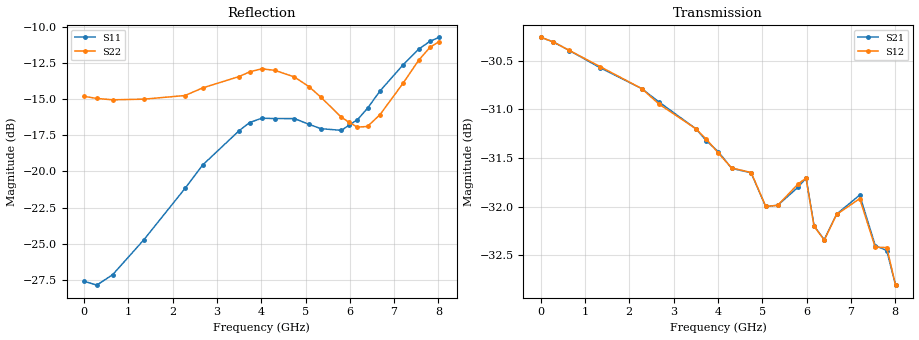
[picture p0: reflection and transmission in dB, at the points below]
! DEVICE ID: PE43712
! File Path: z:\PE43713\PE43713_CHAR_NOM_04292014\AMB\3p300\LS_ATT_29p00dB\PE43713_AMB_3p300V_3p000V_0p000V_LS_ATT_29p00dB_S2P_SN_10_A0139A.s2p
! Serial: 10
! Lot: A0139A
! Temp: 25C
! VDD: 3.300
! VSS: 0.000
! Control_Hi: 3.000
! Control_Lo: 0.000
! Attenuation Step: 29.00dB
! Port 1: RF1
! Port 2: RF2
! ThroughPath:1-2
! IDD: 0.0001456106
! ISS: -1.121e-007
#  Hz  S  RI  R  50
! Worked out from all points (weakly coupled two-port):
!   801 points, 10 MHz to 8.01 GHz, reference 50 ohm
!   highest |S21| = -30.26 dB at 10 MHz (marker M1); lowest = -32.8 dB at 8.01 GHz (marker M2)
!   lowest |S11| = -27.9 dB at 290 MHz (marker M3), VSWR 1.08, Z = 46.3 + j1.23 ohm
!   |S11| at or under -10 dB: start of sweep to end of sweep
!   |S22| runs from -16.9 to -11.0 dB; largest |S21 - S12| = 0.00012
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1e7  -0.0416 0.000898  0.0307 -0.000144  0.0307 -0.000132  -0.1822 0.0013
2.9e8  -0.0381 0.0133  0.0304 -0.00285  0.0304 -0.00286  -0.178 0.0205
6.5e8  -0.0337 0.0281  0.0296 -0.00612  0.0296 -0.00613  -0.1717 0.0441
1.35e9  -0.0209 0.054  0.0272 -0.0117  0.0272 -0.0118  -0.1552 0.0875
2.28e9  0.00952 0.0868  0.0226 -0.018  0.0226 -0.018  -0.1156 0.1424
2.68e9  0.0251 0.1023  0.0202 -0.02  0.0201 -0.02  -0.0944 0.1706
3.5e9  0.0484 0.1297  0.0147 -0.0233  0.0147 -0.0233  -0.0627 0.204
3.74e9  0.0533 0.1379  0.0129 -0.0239  0.013 -0.0239  -0.0578 0.2139
4.01e9  0.0582 0.1415  0.0111 -0.0244  0.011 -0.0244  -0.054 0.2205
4.31e9  0.0617 0.1396  0.00898 -0.0247  0.00902 -0.0247  -0.0451 0.2197
4.75e9  0.072 0.1345  0.00619 -0.0254  0.00623 -0.0254  -0.0317 0.2103
5.08e9  0.0816 0.1207  0.00399 -0.0248  0.00401 -0.0248  -0.021 0.1957
5.35e9  0.0911 0.1073  0.00279 -0.025  0.00277 -0.025  -0.0107 0.1805
5.81e9  0.1136 0.0799  -0.000197 -0.0257  -0.000144 -0.0258  0.0252 0.1521
5.99e9  0.1268 0.0704  -0.00207 -0.0259  -0.00201 -0.0259  0.0432 0.1415
6.17e9  0.1386 0.0602  -0.00347 -0.0243  -0.0034 -0.0243  0.0631 0.1277
6.4e9  0.1574 0.0521  -0.00345 -0.0239  -0.0034 -0.0239  0.0907 0.111
6.68e9  0.1852 0.0435  -0.00493 -0.0244  -0.00488 -0.0244  0.1254 0.0952
7.2e9  0.2315 0.0358  -0.00956 -0.0236  -0.00952 -0.0235  0.1831 0.0859
7.55e9  0.2628 0.0373  -0.0114 -0.0211  -0.0113 -0.0211  0.2256 0.0898
7.81e9  0.2801 0.0406  -0.0125 -0.0203  -0.0125 -0.0204  0.2525 0.0952
8.01e9  0.2886 0.0433  -0.0126 -0.0191  -0.0126 -0.0191  0.2653 0.0953
